VERSION 5.7 ;
  NOWIREEXTENSIONATPIN ON ;
  DIVIDERCHAR "/" ;
  BUSBITCHARS "[]" ;
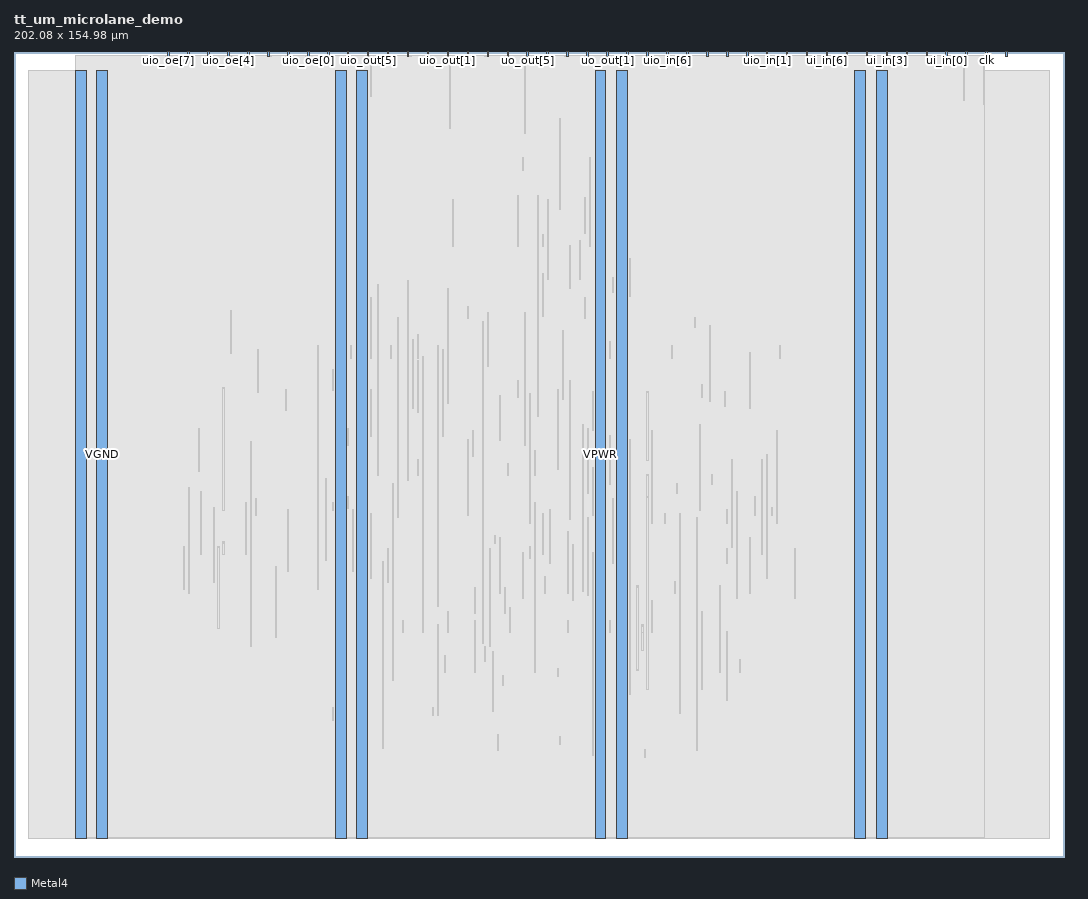
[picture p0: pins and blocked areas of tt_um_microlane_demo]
MACRO tt_um_microlane_demo
  CLASS BLOCK ;
  FOREIGN tt_um_microlane_demo ;
  ORIGIN 0.000 0.000 ;
  SIZE 202.080 BY 154.980 ;
  PIN VPWR
    DIRECTION INOUT ;
    USE POWER ;
    PORT
      LAYER Metal4 ;
        RECT 11.830 3.560 13.930 151.420 ;
    END
    PORT
      LAYER Metal4 ;
        RECT 61.830 3.560 63.930 151.420 ;
    END
    PORT
      LAYER Metal4 ;
        RECT 111.830 3.560 113.930 151.420 ;
    END
    PORT
      LAYER Metal4 ;
        RECT 161.830 3.560 163.930 151.420 ;
    END
  END VPWR
  PIN VGND
    DIRECTION INOUT ;
    USE GROUND ;
    PORT
      LAYER Metal4 ;
        RECT 15.930 3.560 18.030 151.420 ;
    END
    PORT
      LAYER Metal4 ;
        RECT 65.930 3.560 68.030 151.420 ;
    END
    PORT
      LAYER Metal4 ;
        RECT 115.930 3.560 118.030 151.420 ;
    END
    PORT
      LAYER Metal4 ;
        RECT 165.930 3.560 168.030 151.420 ;
    END
  END VGND
  PIN ena
    DIRECTION INPUT ;
    USE SIGNAL ;
    PORT
      LAYER Metal4 ;
        RECT 190.890 153.980 191.190 154.980 ;
    END
  END ena
  PIN clk
    DIRECTION INPUT ;
    USE SIGNAL ;
    PORT
      LAYER Metal4 ;
        RECT 187.050 153.980 187.350 154.980 ;
    END
  END clk
  PIN rst_n
    DIRECTION INPUT ;
    USE SIGNAL ;
    PORT
      LAYER Metal4 ;
        RECT 183.210 153.980 183.510 154.980 ;
    END
  END rst_n
  PIN ui_in[0]
    DIRECTION INPUT ;
    USE SIGNAL ;
    PORT
      LAYER Metal4 ;
        RECT 179.370 153.980 179.670 154.980 ;
    END
  END ui_in[0]
  PIN ui_in[1]
    DIRECTION INPUT ;
    USE SIGNAL ;
    PORT
      LAYER Metal4 ;
        RECT 175.530 153.980 175.830 154.980 ;
    END
  END ui_in[1]
  PIN ui_in[2]
    DIRECTION INPUT ;
    USE SIGNAL ;
    PORT
      LAYER Metal4 ;
        RECT 171.690 153.980 171.990 154.980 ;
    END
  END ui_in[2]
  PIN ui_in[3]
    DIRECTION INPUT ;
    USE SIGNAL ;
    PORT
      LAYER Metal4 ;
        RECT 167.850 153.980 168.150 154.980 ;
    END
  END ui_in[3]
  PIN ui_in[4]
    DIRECTION INPUT ;
    USE SIGNAL ;
    PORT
      LAYER Metal4 ;
        RECT 164.010 153.980 164.310 154.980 ;
    END
  END ui_in[4]
  PIN ui_in[5]
    DIRECTION INPUT ;
    USE SIGNAL ;
    PORT
      LAYER Metal4 ;
        RECT 160.170 153.980 160.470 154.980 ;
    END
  END ui_in[5]
  PIN ui_in[6]
    DIRECTION INPUT ;
    USE SIGNAL ;
    PORT
      LAYER Metal4 ;
        RECT 156.330 153.980 156.630 154.980 ;
    END
  END ui_in[6]
  PIN ui_in[7]
    DIRECTION INPUT ;
    USE SIGNAL ;
    PORT
      LAYER Metal4 ;
        RECT 152.490 153.980 152.790 154.980 ;
    END
  END ui_in[7]
  PIN uio_in[0]
    DIRECTION INPUT ;
    USE SIGNAL ;
    PORT
      LAYER Metal4 ;
        RECT 148.650 153.980 148.950 154.980 ;
    END
  END uio_in[0]
  PIN uio_in[1]
    DIRECTION INPUT ;
    USE SIGNAL ;
    PORT
      LAYER Metal4 ;
        RECT 144.810 153.980 145.110 154.980 ;
    END
  END uio_in[1]
  PIN uio_in[2]
    DIRECTION INPUT ;
    USE SIGNAL ;
    PORT
      LAYER Metal4 ;
        RECT 140.970 153.980 141.270 154.980 ;
    END
  END uio_in[2]
  PIN uio_in[3]
    DIRECTION INPUT ;
    USE SIGNAL ;
    PORT
      LAYER Metal4 ;
        RECT 137.130 153.980 137.430 154.980 ;
    END
  END uio_in[3]
  PIN uio_in[4]
    DIRECTION INPUT ;
    USE SIGNAL ;
    PORT
      LAYER Metal4 ;
        RECT 133.290 153.980 133.590 154.980 ;
    END
  END uio_in[4]
  PIN uio_in[5]
    DIRECTION INPUT ;
    USE SIGNAL ;
    PORT
      LAYER Metal4 ;
        RECT 129.450 153.980 129.750 154.980 ;
    END
  END uio_in[5]
  PIN uio_in[6]
    DIRECTION INPUT ;
    USE SIGNAL ;
    PORT
      LAYER Metal4 ;
        RECT 125.610 153.980 125.910 154.980 ;
    END
  END uio_in[6]
  PIN uio_in[7]
    DIRECTION INPUT ;
    USE SIGNAL ;
    PORT
      LAYER Metal4 ;
        RECT 121.770 153.980 122.070 154.980 ;
    END
  END uio_in[7]
  PIN uo_out[0]
    DIRECTION OUTPUT ;
    USE SIGNAL ;
    PORT
      LAYER Metal4 ;
        RECT 117.930 153.980 118.230 154.980 ;
    END
  END uo_out[0]
  PIN uo_out[1]
    DIRECTION OUTPUT ;
    USE SIGNAL ;
    PORT
      LAYER Metal4 ;
        RECT 114.090 153.980 114.390 154.980 ;
    END
  END uo_out[1]
  PIN uo_out[2]
    DIRECTION OUTPUT ;
    USE SIGNAL ;
    PORT
      LAYER Metal4 ;
        RECT 110.250 153.980 110.550 154.980 ;
    END
  END uo_out[2]
  PIN uo_out[3]
    DIRECTION OUTPUT ;
    USE SIGNAL ;
    PORT
      LAYER Metal4 ;
        RECT 106.410 153.980 106.710 154.980 ;
    END
  END uo_out[3]
  PIN uo_out[4]
    DIRECTION OUTPUT ;
    USE SIGNAL ;
    PORT
      LAYER Metal4 ;
        RECT 102.570 153.980 102.870 154.980 ;
    END
  END uo_out[4]
  PIN uo_out[5]
    DIRECTION OUTPUT ;
    USE SIGNAL ;
    PORT
      LAYER Metal4 ;
        RECT 98.730 153.980 99.030 154.980 ;
    END
  END uo_out[5]
  PIN uo_out[6]
    DIRECTION OUTPUT ;
    USE SIGNAL ;
    PORT
      LAYER Metal4 ;
        RECT 94.890 153.980 95.190 154.980 ;
    END
  END uo_out[6]
  PIN uo_out[7]
    DIRECTION OUTPUT ;
    USE SIGNAL ;
    PORT
      LAYER Metal4 ;
        RECT 91.050 153.980 91.350 154.980 ;
    END
  END uo_out[7]
  PIN uio_out[0]
    DIRECTION OUTPUT ;
    USE SIGNAL ;
    PORT
      LAYER Metal4 ;
        RECT 87.210 153.980 87.510 154.980 ;
    END
  END uio_out[0]
  PIN uio_out[1]
    DIRECTION OUTPUT ;
    USE SIGNAL ;
    PORT
      LAYER Metal4 ;
        RECT 83.370 153.980 83.670 154.980 ;
    END
  END uio_out[1]
  PIN uio_out[2]
    DIRECTION OUTPUT ;
    USE SIGNAL ;
    PORT
      LAYER Metal4 ;
        RECT 79.530 153.980 79.830 154.980 ;
    END
  END uio_out[2]
  PIN uio_out[3]
    DIRECTION OUTPUT ;
    USE SIGNAL ;
    PORT
      LAYER Metal4 ;
        RECT 75.690 153.980 75.990 154.980 ;
    END
  END uio_out[3]
  PIN uio_out[4]
    DIRECTION OUTPUT ;
    USE SIGNAL ;
    PORT
      LAYER Metal4 ;
        RECT 71.850 153.980 72.150 154.980 ;
    END
  END uio_out[4]
  PIN uio_out[5]
    DIRECTION OUTPUT ;
    USE SIGNAL ;
    PORT
      LAYER Metal4 ;
        RECT 68.010 153.980 68.310 154.980 ;
    END
  END uio_out[5]
  PIN uio_out[6]
    DIRECTION OUTPUT ;
    USE SIGNAL ;
    PORT
      LAYER Metal4 ;
        RECT 64.170 153.980 64.470 154.980 ;
    END
  END uio_out[6]
  PIN uio_out[7]
    DIRECTION OUTPUT ;
    USE SIGNAL ;
    PORT
      LAYER Metal4 ;
        RECT 60.330 153.980 60.630 154.980 ;
    END
  END uio_out[7]
  PIN uio_oe[0]
    DIRECTION OUTPUT ;
    USE SIGNAL ;
    PORT
      LAYER Metal4 ;
        RECT 56.490 153.980 56.790 154.980 ;
    END
  END uio_oe[0]
  PIN uio_oe[1]
    DIRECTION OUTPUT ;
    USE SIGNAL ;
    PORT
      LAYER Metal4 ;
        RECT 52.650 153.980 52.950 154.980 ;
    END
  END uio_oe[1]
  PIN uio_oe[2]
    DIRECTION OUTPUT ;
    USE SIGNAL ;
    PORT
      LAYER Metal4 ;
        RECT 48.810 153.980 49.110 154.980 ;
    END
  END uio_oe[2]
  PIN uio_oe[3]
    DIRECTION OUTPUT ;
    USE SIGNAL ;
    PORT
      LAYER Metal4 ;
        RECT 44.970 153.980 45.270 154.980 ;
    END
  END uio_oe[3]
  PIN uio_oe[4]
    DIRECTION OUTPUT ;
    USE SIGNAL ;
    PORT
      LAYER Metal4 ;
        RECT 41.130 153.980 41.430 154.980 ;
    END
  END uio_oe[4]
  PIN uio_oe[5]
    DIRECTION OUTPUT ;
    USE SIGNAL ;
    PORT
      LAYER Metal4 ;
        RECT 37.290 153.980 37.590 154.980 ;
    END
  END uio_oe[5]
  PIN uio_oe[6]
    DIRECTION OUTPUT ;
    USE SIGNAL ;
    PORT
      LAYER Metal4 ;
        RECT 33.450 153.980 33.750 154.980 ;
    END
  END uio_oe[6]
  PIN uio_oe[7]
    DIRECTION OUTPUT ;
    USE SIGNAL ;
    PORT
      LAYER Metal4 ;
        RECT 29.610 153.980 29.910 154.980 ;
    END
  END uio_oe[7]
  OBS
      LAYER GatPoly ;
        RECT 2.880 3.630 199.200 151.350 ;
      LAYER Metal1 ;
        RECT 2.880 3.560 199.200 151.420 ;
      LAYER Metal2 ;
        RECT 11.960 3.635 167.900 154.285 ;
      LAYER Metal3 ;
        RECT 11.915 3.680 186.865 154.320 ;
      LAYER Metal4 ;
        RECT 11.830 3.560 13.930 151.420 ;
        RECT 61.830 3.560 63.930 151.420 ;
        RECT 111.830 3.560 113.930 151.420 ;
        RECT 161.830 3.560 163.930 151.420 ;
        RECT 15.930 3.560 18.030 151.420 ;
        RECT 65.930 3.560 68.030 151.420 ;
        RECT 115.930 3.560 118.030 151.420 ;
        RECT 165.930 3.560 168.030 151.420 ;
        RECT 190.890 153.980 191.190 154.980 ;
        RECT 187.050 153.980 187.350 154.980 ;
        RECT 183.210 153.980 183.510 154.980 ;
        RECT 179.370 153.980 179.670 154.980 ;
        RECT 175.530 153.980 175.830 154.980 ;
        RECT 171.690 153.980 171.990 154.980 ;
        RECT 167.850 153.980 168.150 154.980 ;
        RECT 164.010 153.980 164.310 154.980 ;
        RECT 160.170 153.980 160.470 154.980 ;
        RECT 156.330 153.980 156.630 154.980 ;
        RECT 152.490 153.980 152.790 154.980 ;
        RECT 148.650 153.980 148.950 154.980 ;
        RECT 144.810 153.980 145.110 154.980 ;
        RECT 140.970 153.980 141.270 154.980 ;
        RECT 137.130 153.980 137.430 154.980 ;
        RECT 133.290 153.980 133.590 154.980 ;
        RECT 129.450 153.980 129.750 154.980 ;
        RECT 125.610 153.980 125.910 154.980 ;
        RECT 121.770 153.980 122.070 154.980 ;
        RECT 117.930 153.980 118.230 154.980 ;
        RECT 114.090 153.980 114.390 154.980 ;
        RECT 110.250 153.980 110.550 154.980 ;
        RECT 106.410 153.980 106.710 154.980 ;
        RECT 102.570 153.980 102.870 154.980 ;
        RECT 98.730 153.980 99.030 154.980 ;
        RECT 94.890 153.980 95.190 154.980 ;
        RECT 91.050 153.980 91.350 154.980 ;
        RECT 87.210 153.980 87.510 154.980 ;
        RECT 83.370 153.980 83.670 154.980 ;
        RECT 79.530 153.980 79.830 154.980 ;
        RECT 75.690 153.980 75.990 154.980 ;
        RECT 71.850 153.980 72.150 154.980 ;
        RECT 68.010 153.980 68.310 154.980 ;
        RECT 64.170 153.980 64.470 154.980 ;
        RECT 60.330 153.980 60.630 154.980 ;
        RECT 56.490 153.980 56.790 154.980 ;
        RECT 52.650 153.980 52.950 154.980 ;
        RECT 48.810 153.980 49.110 154.980 ;
        RECT 44.970 153.980 45.270 154.980 ;
        RECT 41.130 153.980 41.430 154.980 ;
        RECT 37.290 153.980 37.590 154.980 ;
        RECT 33.450 153.980 33.750 154.980 ;
        RECT 29.610 153.980 29.910 154.980 ;
        RECT 110.780 134.255 110.980 134.545 ;
        RECT 110.780 117.455 110.980 117.745 ;
        RECT 110.780 117.500 110.980 117.700 ;
        RECT 110.780 117.500 110.980 134.500 ;
        RECT 110.780 134.300 110.980 134.500 ;
        RECT 105.020 141.815 105.220 142.105 ;
        RECT 105.020 124.595 105.220 124.885 ;
        RECT 105.020 124.640 105.220 124.840 ;
        RECT 105.020 124.640 105.220 142.060 ;
        RECT 105.020 141.860 105.220 142.060 ;
        RECT 97.820 134.255 98.020 134.545 ;
        RECT 97.820 132.155 98.020 132.445 ;
        RECT 97.820 132.200 98.020 132.400 ;
        RECT 97.820 132.200 98.020 134.500 ;
        RECT 97.820 134.300 98.020 134.500 ;
        RECT 81.500 27.155 81.700 27.445 ;
        RECT 81.500 27.200 81.700 27.400 ;
        RECT 81.500 27.200 81.700 44.620 ;
        RECT 81.500 33.875 81.700 34.165 ;
        RECT 81.500 33.920 81.700 34.120 ;
        RECT 81.500 44.375 81.700 44.665 ;
        RECT 81.500 44.420 81.700 44.620 ;
        RECT 82.940 35.555 83.140 35.845 ;
        RECT 82.940 35.600 83.140 35.800 ;
        RECT 82.940 35.600 83.140 38.740 ;
        RECT 82.940 38.495 83.140 38.785 ;
        RECT 82.940 38.540 83.140 38.740 ;
        RECT 139.580 35.555 139.780 35.845 ;
        RECT 139.580 35.600 139.780 35.800 ;
        RECT 139.580 35.600 139.780 37.900 ;
        RECT 139.580 37.655 139.780 37.945 ;
        RECT 139.580 37.700 139.780 37.900 ;
        RECT 104.540 35.975 104.740 36.265 ;
        RECT 104.540 34.715 104.740 35.005 ;
        RECT 104.540 34.760 104.740 34.960 ;
        RECT 104.540 34.760 104.740 36.220 ;
        RECT 104.540 36.020 104.740 36.220 ;
        RECT 80.540 28.415 80.740 28.705 ;
        RECT 80.540 27.155 80.740 27.445 ;
        RECT 80.540 27.200 80.740 27.400 ;
        RECT 80.540 27.200 80.740 28.660 ;
        RECT 80.540 28.460 80.740 28.660 ;
        RECT 114.620 43.115 114.820 43.405 ;
        RECT 114.620 43.160 114.820 43.360 ;
        RECT 114.620 43.160 114.820 45.460 ;
        RECT 114.620 45.215 114.820 45.505 ;
        RECT 114.620 45.260 114.820 45.460 ;
        RECT 137.180 59.075 137.380 59.365 ;
        RECT 137.180 56.555 137.380 56.845 ;
        RECT 137.180 56.600 137.380 56.800 ;
        RECT 137.180 56.600 137.380 59.320 ;
        RECT 137.180 59.120 137.380 59.320 ;
        RECT 61.340 28.415 61.540 28.705 ;
        RECT 61.340 26.315 61.540 26.605 ;
        RECT 61.340 26.360 61.540 26.560 ;
        RECT 61.340 26.360 61.540 28.660 ;
        RECT 61.340 28.460 61.540 28.660 ;
        RECT 91.580 43.115 91.780 43.405 ;
        RECT 91.580 40.595 91.780 40.885 ;
        RECT 91.580 40.640 91.780 40.840 ;
        RECT 91.580 40.640 91.780 43.360 ;
        RECT 91.580 43.160 91.780 43.360 ;
        RECT 91.580 43.160 91.780 59.320 ;
        RECT 91.580 59.075 91.780 59.365 ;
        RECT 91.580 59.120 91.780 59.320 ;
        RECT 137.180 43.115 137.380 43.405 ;
        RECT 137.180 30.095 137.380 30.385 ;
        RECT 137.180 30.140 137.380 30.340 ;
        RECT 137.180 30.140 137.380 43.360 ;
        RECT 137.180 40.595 137.380 40.885 ;
        RECT 137.180 40.640 137.380 40.840 ;
        RECT 137.180 43.160 137.380 43.360 ;
        RECT 122.780 43.115 122.980 43.405 ;
        RECT 122.780 43.160 122.980 43.360 ;
        RECT 122.780 43.160 122.980 49.240 ;
        RECT 122.780 48.995 122.980 49.285 ;
        RECT 122.780 49.040 122.980 49.240 ;
        RECT 127.100 50.675 127.300 50.965 ;
        RECT 127.100 50.720 127.300 50.920 ;
        RECT 127.100 50.720 127.300 53.020 ;
        RECT 127.100 52.775 127.300 53.065 ;
        RECT 127.100 52.820 127.300 53.020 ;
        RECT 150.140 59.075 150.340 59.365 ;
        RECT 150.140 49.835 150.340 50.125 ;
        RECT 150.140 49.880 150.340 50.080 ;
        RECT 150.140 49.880 150.340 59.320 ;
        RECT 150.140 52.775 150.340 53.065 ;
        RECT 150.140 52.820 150.340 53.020 ;
        RECT 150.140 59.120 150.340 59.320 ;
        RECT 108.860 111.155 109.060 111.445 ;
        RECT 108.860 111.200 109.060 111.400 ;
        RECT 108.860 111.200 109.060 118.540 ;
        RECT 108.860 118.295 109.060 118.585 ;
        RECT 108.860 118.340 109.060 118.540 ;
        RECT 115.100 111.155 115.300 111.445 ;
        RECT 115.100 108.635 115.300 108.925 ;
        RECT 115.100 108.680 115.300 108.880 ;
        RECT 115.100 108.680 115.300 111.400 ;
        RECT 115.100 111.200 115.300 111.400 ;
        RECT 102.620 111.155 102.820 111.445 ;
        RECT 102.620 111.200 102.820 111.400 ;
        RECT 102.620 111.200 102.820 116.440 ;
        RECT 102.620 116.195 102.820 116.485 ;
        RECT 102.620 116.240 102.820 116.440 ;
        RECT 102.620 116.240 102.820 126.520 ;
        RECT 102.620 123.755 102.820 124.045 ;
        RECT 102.620 123.800 102.820 124.000 ;
        RECT 102.620 126.275 102.820 126.565 ;
        RECT 102.620 126.320 102.820 126.520 ;
        RECT 120.860 43.115 121.060 43.405 ;
        RECT 120.860 39.755 121.060 40.045 ;
        RECT 120.860 39.800 121.060 40.000 ;
        RECT 120.860 39.800 121.060 43.360 ;
        RECT 120.860 43.160 121.060 43.360 ;
        RECT 120.860 43.160 121.060 44.620 ;
        RECT 120.860 44.375 121.060 44.665 ;
        RECT 120.860 44.420 121.060 44.620 ;
        RECT 64.700 96.035 64.900 96.325 ;
        RECT 64.700 96.080 64.900 96.280 ;
        RECT 64.700 96.080 64.900 98.380 ;
        RECT 64.700 98.135 64.900 98.425 ;
        RECT 64.700 98.180 64.900 98.380 ;
        RECT 105.500 96.035 105.700 96.325 ;
        RECT 105.500 88.055 105.700 88.345 ;
        RECT 105.500 88.100 105.700 88.300 ;
        RECT 105.500 88.100 105.700 96.280 ;
        RECT 105.500 96.080 105.700 96.280 ;
        RECT 105.500 96.080 105.700 101.320 ;
        RECT 105.500 101.075 105.700 101.365 ;
        RECT 105.500 101.120 105.700 101.320 ;
        RECT 132.380 88.475 132.580 88.765 ;
        RECT 132.380 88.520 132.580 88.720 ;
        RECT 132.380 88.520 132.580 90.820 ;
        RECT 132.380 90.575 132.580 90.865 ;
        RECT 132.380 90.620 132.580 90.820 ;
        RECT 74.780 43.115 74.980 43.405 ;
        RECT 74.780 43.160 74.980 43.360 ;
        RECT 74.780 43.160 74.980 45.460 ;
        RECT 74.780 45.215 74.980 45.505 ;
        RECT 74.780 45.260 74.980 45.460 ;
        RECT 88.700 35.555 88.900 35.845 ;
        RECT 88.700 35.600 88.900 35.800 ;
        RECT 88.700 35.600 88.900 45.460 ;
        RECT 88.700 45.215 88.900 45.505 ;
        RECT 88.700 45.260 88.900 45.460 ;
        RECT 101.660 58.235 101.860 58.525 ;
        RECT 101.660 58.280 101.860 58.480 ;
        RECT 101.660 58.280 101.860 66.040 ;
        RECT 101.660 65.795 101.860 66.085 ;
        RECT 101.660 65.840 101.860 66.040 ;
        RECT 83.420 43.115 83.620 43.405 ;
        RECT 83.420 43.160 83.620 43.360 ;
        RECT 83.420 43.160 83.620 47.140 ;
        RECT 83.420 46.895 83.620 47.185 ;
        RECT 83.420 46.940 83.620 47.140 ;
        RECT 88.700 51.515 88.900 51.805 ;
        RECT 88.700 46.895 88.900 47.185 ;
        RECT 88.700 46.940 88.900 47.140 ;
        RECT 88.700 46.940 88.900 51.760 ;
        RECT 88.700 51.560 88.900 51.760 ;
        RECT 111.260 89.315 111.460 89.605 ;
        RECT 111.260 82.175 111.460 82.465 ;
        RECT 111.260 82.220 111.460 82.420 ;
        RECT 111.260 82.220 111.460 89.560 ;
        RECT 111.260 89.360 111.460 89.560 ;
        RECT 146.780 81.755 146.980 82.045 ;
        RECT 146.780 64.115 146.980 64.405 ;
        RECT 146.780 64.160 146.980 64.360 ;
        RECT 146.780 64.160 146.980 82.000 ;
        RECT 146.780 75.455 146.980 75.745 ;
        RECT 146.780 75.500 146.980 75.700 ;
        RECT 146.780 81.800 146.980 82.000 ;
        RECT 68.540 65.795 68.740 66.085 ;
        RECT 68.540 53.615 68.740 53.905 ;
        RECT 68.540 53.660 68.740 53.860 ;
        RECT 68.540 53.660 68.740 66.040 ;
        RECT 68.540 65.840 68.740 66.040 ;
        RECT 102.140 50.675 102.340 50.965 ;
        RECT 102.140 50.720 102.340 50.920 ;
        RECT 102.140 50.720 102.340 53.860 ;
        RECT 102.140 53.615 102.340 53.905 ;
        RECT 102.140 53.660 102.340 53.860 ;
        RECT 95.420 43.115 95.620 43.405 ;
        RECT 95.420 43.160 95.620 43.360 ;
        RECT 95.420 43.160 95.620 47.980 ;
        RECT 95.420 47.735 95.620 48.025 ;
        RECT 95.420 47.780 95.620 47.980 ;
        RECT 121.820 89.315 122.020 89.605 ;
        RECT 121.820 76.295 122.020 76.585 ;
        RECT 121.820 76.340 122.020 76.540 ;
        RECT 121.820 76.340 122.020 89.560 ;
        RECT 121.820 89.360 122.020 89.560 ;
        RECT 138.140 74.195 138.340 74.485 ;
        RECT 138.140 59.495 138.340 59.785 ;
        RECT 138.140 59.540 138.340 59.740 ;
        RECT 138.140 59.540 138.340 74.440 ;
        RECT 138.140 74.240 138.340 74.440 ;
        RECT 138.140 74.240 138.340 76.540 ;
        RECT 138.140 76.295 138.340 76.585 ;
        RECT 138.140 76.340 138.340 76.540 ;
        RECT 145.820 65.795 146.020 66.085 ;
        RECT 145.820 65.840 146.020 66.040 ;
        RECT 145.820 65.840 146.020 67.300 ;
        RECT 145.820 67.055 146.020 67.345 ;
        RECT 145.820 67.100 146.020 67.300 ;
        RECT 93.020 20.435 93.220 20.725 ;
        RECT 93.020 20.480 93.220 20.680 ;
        RECT 93.020 20.480 93.220 23.620 ;
        RECT 93.020 23.375 93.220 23.665 ;
        RECT 93.020 23.420 93.220 23.620 ;
        RECT 106.460 50.675 106.660 50.965 ;
        RECT 106.460 50.720 106.660 50.920 ;
        RECT 106.460 50.720 106.660 62.680 ;
        RECT 106.460 62.435 106.660 62.725 ;
        RECT 106.460 62.480 106.660 62.680 ;
        RECT 88.220 81.755 88.420 82.045 ;
        RECT 88.220 77.135 88.420 77.425 ;
        RECT 88.220 77.180 88.420 77.380 ;
        RECT 88.220 77.180 88.420 82.000 ;
        RECT 88.220 81.800 88.420 82.000 ;
        RECT 144.860 74.195 145.060 74.485 ;
        RECT 144.860 53.615 145.060 53.905 ;
        RECT 144.860 53.660 145.060 53.860 ;
        RECT 144.860 53.660 145.060 74.440 ;
        RECT 144.860 74.240 145.060 74.440 ;
        RECT 144.860 74.240 145.060 77.380 ;
        RECT 144.860 77.135 145.060 77.425 ;
        RECT 144.860 77.180 145.060 77.380 ;
        RECT 143.900 58.235 144.100 58.525 ;
        RECT 143.900 58.280 144.100 58.480 ;
        RECT 143.900 58.280 144.100 76.540 ;
        RECT 143.900 76.295 144.100 76.585 ;
        RECT 143.900 76.340 144.100 76.540 ;
        RECT 50.300 50.675 50.500 50.965 ;
        RECT 50.300 42.275 50.500 42.565 ;
        RECT 50.300 42.320 50.500 42.520 ;
        RECT 50.300 42.320 50.500 50.920 ;
        RECT 50.300 50.720 50.500 50.920 ;
        RECT 50.300 50.720 50.500 55.960 ;
        RECT 50.300 55.715 50.500 56.005 ;
        RECT 50.300 55.760 50.500 55.960 ;
        RECT 94.460 51.515 94.660 51.805 ;
        RECT 94.460 46.895 94.660 47.185 ;
        RECT 94.460 46.940 94.660 47.140 ;
        RECT 94.460 46.940 94.660 51.760 ;
        RECT 94.460 51.560 94.660 51.760 ;
        RECT 122.780 81.755 122.980 82.045 ;
        RECT 122.780 64.115 122.980 64.405 ;
        RECT 122.780 64.160 122.980 64.360 ;
        RECT 122.780 64.160 122.980 82.000 ;
        RECT 122.780 81.800 122.980 82.000 ;
        RECT 111.260 58.235 111.460 58.525 ;
        RECT 111.260 19.595 111.460 19.885 ;
        RECT 111.260 19.640 111.460 19.840 ;
        RECT 111.260 19.640 111.460 58.480 ;
        RECT 111.260 32.195 111.460 32.485 ;
        RECT 111.260 32.240 111.460 32.440 ;
        RECT 111.260 58.280 111.460 58.480 ;
        RECT 121.340 19.175 121.540 19.465 ;
        RECT 121.340 19.220 121.540 19.420 ;
        RECT 121.340 19.220 121.540 20.680 ;
        RECT 121.340 20.435 121.540 20.725 ;
        RECT 121.340 20.480 121.540 20.680 ;
        RECT 131.420 58.235 131.620 58.525 ;
        RECT 131.420 20.435 131.620 20.725 ;
        RECT 131.420 20.480 131.620 20.680 ;
        RECT 131.420 20.480 131.620 58.480 ;
        RECT 131.420 58.280 131.620 58.480 ;
        RECT 131.420 58.280 131.620 65.200 ;
        RECT 131.420 64.955 131.620 65.245 ;
        RECT 131.420 65.000 131.620 65.200 ;
        RECT 93.500 50.675 93.700 50.965 ;
        RECT 93.500 50.720 93.700 50.920 ;
        RECT 93.500 50.720 93.700 59.740 ;
        RECT 93.500 59.495 93.700 59.785 ;
        RECT 93.500 59.540 93.700 59.740 ;
        RECT 93.500 59.540 93.700 61.420 ;
        RECT 93.500 61.175 93.700 61.465 ;
        RECT 93.500 61.220 93.700 61.420 ;
        RECT 141.500 58.235 141.700 58.525 ;
        RECT 141.500 50.675 141.700 50.965 ;
        RECT 141.500 50.720 141.700 50.920 ;
        RECT 141.500 50.720 141.700 58.480 ;
        RECT 141.500 58.280 141.700 58.480 ;
        RECT 141.500 58.280 141.700 61.420 ;
        RECT 141.500 61.175 141.700 61.465 ;
        RECT 141.500 61.220 141.700 61.420 ;
        RECT 137.180 66.635 137.380 66.925 ;
        RECT 137.180 64.115 137.380 64.405 ;
        RECT 137.180 64.160 137.380 64.360 ;
        RECT 137.180 64.160 137.380 66.880 ;
        RECT 137.180 66.680 137.380 66.880 ;
        RECT 134.300 73.355 134.500 73.645 ;
        RECT 134.300 71.675 134.500 71.965 ;
        RECT 134.300 71.720 134.500 71.920 ;
        RECT 134.300 71.720 134.500 73.600 ;
        RECT 134.300 73.400 134.500 73.600 ;
        RECT 33.500 50.675 33.700 50.965 ;
        RECT 33.500 50.720 33.700 50.920 ;
        RECT 33.500 50.720 33.700 71.080 ;
        RECT 33.500 70.835 33.700 71.125 ;
        RECT 33.500 70.880 33.700 71.080 ;
        RECT 128.060 35.555 128.260 35.845 ;
        RECT 128.060 27.575 128.260 27.865 ;
        RECT 128.060 27.620 128.260 27.820 ;
        RECT 128.060 27.620 128.260 35.800 ;
        RECT 128.060 35.600 128.260 35.800 ;
        RECT 128.060 35.600 128.260 66.040 ;
        RECT 128.060 65.795 128.260 66.085 ;
        RECT 128.060 65.840 128.260 66.040 ;
        RECT 135.740 35.555 135.940 35.845 ;
        RECT 135.740 35.600 135.940 35.800 ;
        RECT 135.740 35.600 135.940 52.180 ;
        RECT 135.740 51.935 135.940 52.225 ;
        RECT 135.740 51.980 135.940 52.180 ;
        RECT 35.900 58.235 36.100 58.525 ;
        RECT 35.900 58.280 36.100 58.480 ;
        RECT 35.900 58.280 36.100 70.240 ;
        RECT 35.900 69.995 36.100 70.285 ;
        RECT 35.900 70.040 36.100 70.240 ;
        RECT 107.420 59.915 107.620 60.205 ;
        RECT 107.420 49.415 107.620 49.705 ;
        RECT 107.420 49.460 107.620 49.660 ;
        RECT 107.420 49.460 107.620 60.160 ;
        RECT 107.420 59.960 107.620 60.160 ;
        RECT 45.500 73.355 45.700 73.645 ;
        RECT 45.500 40.595 45.700 40.885 ;
        RECT 45.500 40.640 45.700 40.840 ;
        RECT 45.500 40.640 45.700 73.600 ;
        RECT 45.500 73.400 45.700 73.600 ;
        RECT 45.500 73.400 45.700 79.900 ;
        RECT 45.500 79.655 45.700 79.945 ;
        RECT 45.500 79.700 45.700 79.900 ;
        RECT 118.460 50.675 118.660 50.965 ;
        RECT 118.460 31.355 118.660 31.645 ;
        RECT 118.460 31.400 118.660 31.600 ;
        RECT 118.460 31.400 118.660 50.920 ;
        RECT 118.460 50.720 118.660 50.920 ;
        RECT 118.460 50.720 118.660 80.320 ;
        RECT 118.460 80.075 118.660 80.365 ;
        RECT 118.460 80.120 118.660 80.320 ;
        RECT 40.220 58.235 40.420 58.525 ;
        RECT 40.220 58.280 40.420 58.480 ;
        RECT 40.220 58.280 40.420 60.580 ;
        RECT 40.220 60.335 40.420 60.625 ;
        RECT 40.220 60.380 40.420 60.580 ;
        RECT 96.860 88.475 97.060 88.765 ;
        RECT 96.860 88.520 97.060 88.720 ;
        RECT 96.860 88.520 97.060 91.660 ;
        RECT 96.860 91.415 97.060 91.705 ;
        RECT 96.860 91.460 97.060 91.660 ;
        RECT 106.940 80.915 107.140 81.205 ;
        RECT 106.940 64.955 107.140 65.245 ;
        RECT 106.940 65.000 107.140 65.200 ;
        RECT 106.940 65.000 107.140 81.160 ;
        RECT 106.940 80.960 107.140 81.160 ;
        RECT 106.940 80.960 107.140 91.660 ;
        RECT 106.940 91.415 107.140 91.705 ;
        RECT 106.940 91.460 107.140 91.660 ;
        RECT 110.300 50.255 110.500 50.545 ;
        RECT 110.300 50.300 110.500 50.500 ;
        RECT 110.300 50.300 110.500 65.200 ;
        RECT 110.300 64.955 110.500 65.245 ;
        RECT 110.300 65.000 110.500 65.200 ;
        RECT 106.460 43.115 106.660 43.405 ;
        RECT 106.460 43.160 106.660 43.360 ;
        RECT 106.460 43.160 106.660 45.460 ;
        RECT 106.460 45.215 106.660 45.505 ;
        RECT 106.460 45.260 106.660 45.460 ;
        RECT 114.620 80.915 114.820 81.205 ;
        RECT 114.620 71.675 114.820 71.965 ;
        RECT 114.620 71.720 114.820 71.920 ;
        RECT 114.620 71.720 114.820 81.160 ;
        RECT 114.620 80.960 114.820 81.160 ;
        RECT 94.940 73.355 95.140 73.645 ;
        RECT 94.940 73.400 95.140 73.600 ;
        RECT 94.940 73.400 95.140 75.700 ;
        RECT 94.940 75.455 95.140 75.745 ;
        RECT 94.940 75.500 95.140 75.700 ;
        RECT 44.540 58.235 44.740 58.525 ;
        RECT 44.540 58.280 44.740 58.480 ;
        RECT 44.540 58.280 44.740 68.140 ;
        RECT 44.540 67.895 44.740 68.185 ;
        RECT 44.540 67.940 44.740 68.140 ;
        RECT 87.260 65.795 87.460 66.085 ;
        RECT 87.260 65.840 87.460 66.040 ;
        RECT 87.260 65.840 87.460 80.320 ;
        RECT 87.260 80.075 87.460 80.365 ;
        RECT 87.260 80.120 87.460 80.320 ;
        RECT 93.500 88.475 93.700 88.765 ;
        RECT 93.500 80.075 93.700 80.365 ;
        RECT 93.500 80.120 93.700 80.320 ;
        RECT 93.500 80.120 93.700 88.720 ;
        RECT 93.500 88.520 93.700 88.720 ;
        RECT 77.660 73.355 77.860 73.645 ;
        RECT 77.660 73.400 77.860 73.600 ;
        RECT 77.660 73.400 77.860 76.540 ;
        RECT 77.660 76.295 77.860 76.585 ;
        RECT 77.660 76.340 77.860 76.540 ;
        RECT 46.460 65.795 46.660 66.085 ;
        RECT 46.460 65.840 46.660 66.040 ;
        RECT 46.460 65.840 46.660 68.980 ;
        RECT 46.460 68.735 46.660 69.025 ;
        RECT 46.460 68.780 46.660 68.980 ;
        RECT 97.820 58.235 98.020 58.525 ;
        RECT 97.820 49.835 98.020 50.125 ;
        RECT 97.820 49.880 98.020 50.080 ;
        RECT 97.820 49.880 98.020 58.480 ;
        RECT 97.820 58.280 98.020 58.480 ;
        RECT 92.540 61.595 92.740 61.885 ;
        RECT 92.540 60.335 92.740 60.625 ;
        RECT 92.540 60.380 92.740 60.580 ;
        RECT 92.540 60.380 92.740 61.840 ;
        RECT 92.540 61.640 92.740 61.840 ;
        RECT 77.660 96.035 77.860 96.325 ;
        RECT 77.660 96.080 77.860 96.280 ;
        RECT 77.660 96.080 77.860 100.480 ;
        RECT 77.660 100.235 77.860 100.525 ;
        RECT 77.660 100.280 77.860 100.480 ;
        RECT 78.620 43.115 78.820 43.405 ;
        RECT 78.620 43.160 78.820 43.360 ;
        RECT 78.620 43.160 78.820 96.280 ;
        RECT 78.620 96.035 78.820 96.325 ;
        RECT 78.620 96.080 78.820 96.280 ;
        RECT 91.100 104.435 91.300 104.725 ;
        RECT 91.100 94.355 91.300 94.645 ;
        RECT 91.100 94.400 91.300 94.600 ;
        RECT 91.100 94.400 91.300 104.680 ;
        RECT 91.100 104.480 91.300 104.680 ;
        RECT 87.260 103.595 87.460 103.885 ;
        RECT 87.260 103.640 87.460 103.840 ;
        RECT 87.260 103.640 87.460 105.940 ;
        RECT 87.260 105.695 87.460 105.985 ;
        RECT 87.260 105.740 87.460 105.940 ;
        RECT 83.420 96.035 83.620 96.325 ;
        RECT 83.420 87.215 83.620 87.505 ;
        RECT 83.420 87.260 83.620 87.460 ;
        RECT 83.420 87.260 83.620 96.280 ;
        RECT 83.420 96.080 83.620 96.280 ;
        RECT 83.420 96.080 83.620 109.300 ;
        RECT 83.420 109.055 83.620 109.345 ;
        RECT 83.420 109.100 83.620 109.300 ;
        RECT 114.620 96.035 114.820 96.325 ;
        RECT 114.620 96.080 114.820 96.280 ;
        RECT 114.620 96.080 114.820 99.220 ;
        RECT 114.620 98.975 114.820 99.265 ;
        RECT 114.620 99.020 114.820 99.220 ;
        RECT 77.660 88.475 77.860 88.765 ;
        RECT 77.660 85.535 77.860 85.825 ;
        RECT 77.660 85.580 77.860 85.780 ;
        RECT 77.660 85.580 77.860 88.720 ;
        RECT 77.660 88.520 77.860 88.720 ;
        RECT 77.660 88.520 77.860 95.440 ;
        RECT 77.660 95.195 77.860 95.485 ;
        RECT 77.660 95.240 77.860 95.440 ;
        RECT 76.700 96.875 76.900 97.165 ;
        RECT 76.700 86.375 76.900 86.665 ;
        RECT 76.700 86.420 76.900 86.620 ;
        RECT 76.700 86.420 76.900 97.120 ;
        RECT 76.700 96.920 76.900 97.120 ;
        RECT 76.700 96.920 76.900 99.640 ;
        RECT 76.700 99.395 76.900 99.685 ;
        RECT 76.700 99.440 76.900 99.640 ;
        RECT 72.380 96.035 72.580 96.325 ;
        RECT 72.380 96.080 72.580 96.280 ;
        RECT 72.380 96.080 72.580 98.380 ;
        RECT 72.380 98.135 72.580 98.425 ;
        RECT 72.380 98.180 72.580 98.380 ;
        RECT 61.340 89.735 61.540 90.025 ;
        RECT 61.340 89.780 61.540 89.980 ;
        RECT 61.340 89.780 61.540 93.760 ;
        RECT 61.340 93.515 61.540 93.805 ;
        RECT 61.340 93.560 61.540 93.760 ;
        RECT 136.700 89.315 136.900 89.605 ;
        RECT 136.700 86.795 136.900 87.085 ;
        RECT 136.700 86.840 136.900 87.040 ;
        RECT 136.700 86.840 136.900 89.560 ;
        RECT 136.700 89.360 136.900 89.560 ;
        RECT 126.620 96.035 126.820 96.325 ;
        RECT 126.620 96.080 126.820 96.280 ;
        RECT 126.620 96.080 126.820 98.380 ;
        RECT 126.620 98.135 126.820 98.425 ;
        RECT 126.620 98.180 126.820 98.380 ;
        RECT 141.500 96.875 141.700 97.165 ;
        RECT 141.500 86.375 141.700 86.665 ;
        RECT 141.500 86.420 141.700 86.620 ;
        RECT 141.500 86.420 141.700 97.120 ;
        RECT 141.500 96.920 141.700 97.120 ;
        RECT 147.260 96.035 147.460 96.325 ;
        RECT 147.260 96.080 147.460 96.280 ;
        RECT 147.260 96.080 147.460 98.380 ;
        RECT 147.260 98.135 147.460 98.425 ;
        RECT 147.260 98.180 147.460 98.380 ;
        RECT 40.220 66.635 40.420 66.925 ;
        RECT 40.220 66.680 40.420 66.880 ;
        RECT 40.220 66.680 40.420 90.400 ;
        RECT 40.220 90.155 40.420 90.445 ;
        RECT 40.220 90.200 40.420 90.400 ;
        RECT 41.660 96.875 41.860 97.165 ;
        RECT 41.660 96.920 41.860 97.120 ;
        RECT 41.660 96.920 41.860 105.100 ;
        RECT 41.660 104.855 41.860 105.145 ;
        RECT 41.660 104.900 41.860 105.100 ;
        RECT 82.460 80.915 82.660 81.205 ;
        RECT 82.460 80.960 82.660 81.160 ;
        RECT 82.460 80.960 82.660 97.540 ;
        RECT 82.460 97.295 82.660 97.585 ;
        RECT 82.460 97.340 82.660 97.540 ;
        RECT 64.220 79.235 64.420 79.525 ;
        RECT 64.220 79.280 64.420 79.480 ;
        RECT 64.220 79.280 64.420 82.420 ;
        RECT 64.220 82.175 64.420 82.465 ;
        RECT 64.220 82.220 64.420 82.420 ;
        RECT 68.540 80.915 68.740 81.205 ;
        RECT 68.540 80.960 68.740 81.160 ;
        RECT 68.540 80.960 68.740 89.980 ;
        RECT 68.540 89.735 68.740 90.025 ;
        RECT 68.540 89.780 68.740 89.980 ;
        RECT 46.940 89.315 47.140 89.605 ;
        RECT 46.940 89.360 47.140 89.560 ;
        RECT 46.940 89.360 47.140 97.540 ;
        RECT 46.940 97.295 47.140 97.585 ;
        RECT 46.940 97.340 47.140 97.540 ;
        RECT 109.340 51.095 109.540 51.385 ;
        RECT 109.340 51.140 109.540 51.340 ;
        RECT 109.340 51.140 109.540 83.260 ;
        RECT 109.340 83.015 109.540 83.305 ;
        RECT 109.340 83.060 109.540 83.260 ;
        RECT 100.220 35.555 100.420 35.845 ;
        RECT 100.220 35.600 100.420 35.800 ;
        RECT 100.220 35.600 100.420 68.140 ;
        RECT 100.220 67.895 100.420 68.185 ;
        RECT 100.220 67.940 100.420 68.140 ;
        RECT 39.260 43.955 39.460 44.245 ;
        RECT 39.260 44.000 39.460 44.200 ;
        RECT 39.260 44.000 39.460 59.740 ;
        RECT 39.260 59.495 39.460 59.785 ;
        RECT 39.260 59.540 39.460 59.740 ;
        RECT 52.220 85.955 52.420 86.245 ;
        RECT 52.220 86.000 52.420 86.200 ;
        RECT 52.220 86.000 52.420 89.980 ;
        RECT 52.220 89.735 52.420 90.025 ;
        RECT 52.220 89.780 52.420 89.980 ;
        RECT 110.300 69.995 110.500 70.285 ;
        RECT 110.300 70.040 110.500 70.240 ;
        RECT 110.300 70.040 110.500 82.420 ;
        RECT 110.300 82.175 110.500 82.465 ;
        RECT 110.300 82.220 110.500 82.420 ;
        RECT 104.540 74.615 104.740 74.905 ;
        RECT 104.540 74.660 104.740 74.860 ;
        RECT 104.540 74.660 104.740 89.980 ;
        RECT 104.540 89.735 104.740 90.025 ;
        RECT 104.540 89.780 104.740 89.980 ;
        RECT 119.900 35.975 120.100 36.265 ;
        RECT 119.900 36.020 120.100 36.220 ;
        RECT 119.900 36.020 120.100 52.180 ;
        RECT 119.900 51.935 120.100 52.225 ;
        RECT 119.900 51.980 120.100 52.180 ;
        RECT 35.420 74.195 35.620 74.485 ;
        RECT 35.420 74.240 35.620 74.440 ;
        RECT 35.420 74.240 35.620 82.420 ;
        RECT 35.420 82.175 35.620 82.465 ;
        RECT 35.420 82.220 35.620 82.420 ;
        RECT 32.540 51.515 32.740 51.805 ;
        RECT 32.540 51.560 32.740 51.760 ;
        RECT 32.540 51.560 32.740 59.740 ;
        RECT 32.540 59.495 32.740 59.785 ;
        RECT 32.540 59.540 32.740 59.740 ;
        RECT 131.900 66.635 132.100 66.925 ;
        RECT 131.900 66.680 132.100 66.880 ;
        RECT 131.900 66.680 132.100 83.260 ;
        RECT 131.900 83.015 132.100 83.305 ;
        RECT 131.900 83.060 132.100 83.260 ;
        RECT 111.260 65.795 111.460 66.085 ;
        RECT 111.260 65.840 111.460 66.040 ;
        RECT 111.260 65.840 111.460 74.860 ;
        RECT 111.260 74.615 111.460 74.905 ;
        RECT 111.260 74.660 111.460 74.860 ;
        RECT 38.300 52.775 38.500 53.065 ;
        RECT 38.300 52.820 38.500 53.020 ;
        RECT 38.300 52.820 38.500 67.300 ;
        RECT 38.300 67.055 38.500 67.345 ;
        RECT 38.300 67.100 38.500 67.300 ;
        RECT 105.020 22.955 105.220 23.245 ;
        RECT 105.020 21.695 105.220 21.985 ;
        RECT 105.020 21.740 105.220 21.940 ;
        RECT 105.020 21.740 105.220 23.200 ;
        RECT 105.020 23.000 105.220 23.200 ;
        RECT 52.700 66.635 52.900 66.925 ;
        RECT 52.700 54.875 52.900 55.165 ;
        RECT 52.700 54.920 52.900 55.120 ;
        RECT 52.700 54.920 52.900 66.880 ;
        RECT 52.700 66.680 52.900 66.880 ;
        RECT 125.180 65.795 125.380 66.085 ;
        RECT 125.180 64.115 125.380 64.405 ;
        RECT 125.180 64.160 125.380 64.360 ;
        RECT 125.180 64.160 125.380 66.040 ;
        RECT 125.180 65.840 125.380 66.040 ;
        RECT 65.180 66.635 65.380 66.925 ;
        RECT 65.180 54.875 65.380 55.165 ;
        RECT 65.180 54.920 65.380 55.120 ;
        RECT 65.180 54.920 65.380 66.880 ;
        RECT 65.180 66.680 65.380 66.880 ;
        RECT 61.340 66.635 61.540 66.925 ;
        RECT 61.340 66.680 61.540 66.880 ;
        RECT 61.340 66.680 61.540 68.140 ;
        RECT 61.340 67.895 61.540 68.185 ;
        RECT 61.340 67.940 61.540 68.140 ;
        RECT 71.900 59.075 72.100 59.365 ;
        RECT 71.900 52.775 72.100 53.065 ;
        RECT 71.900 52.820 72.100 53.020 ;
        RECT 71.900 52.820 72.100 59.320 ;
        RECT 71.900 59.120 72.100 59.320 ;
        RECT 99.260 59.495 99.460 59.785 ;
        RECT 99.260 57.395 99.460 57.685 ;
        RECT 99.260 57.440 99.460 57.640 ;
        RECT 99.260 57.440 99.460 59.740 ;
        RECT 99.260 59.540 99.460 59.740 ;
        RECT 64.220 69.155 64.420 69.445 ;
        RECT 64.220 67.055 64.420 67.345 ;
        RECT 64.220 67.100 64.420 67.300 ;
        RECT 64.220 67.100 64.420 69.400 ;
        RECT 64.220 69.200 64.420 69.400 ;
        RECT 103.100 66.635 103.300 66.925 ;
        RECT 103.100 56.555 103.300 56.845 ;
        RECT 103.100 56.600 103.300 56.800 ;
        RECT 103.100 56.600 103.300 66.880 ;
        RECT 103.100 66.680 103.300 66.880 ;
        RECT 115.100 56.555 115.300 56.845 ;
        RECT 115.100 56.600 115.300 56.800 ;
        RECT 115.100 56.600 115.300 68.980 ;
        RECT 115.100 68.735 115.300 69.025 ;
        RECT 115.100 68.780 115.300 68.980 ;
        RECT 90.140 102.755 90.340 103.045 ;
        RECT 90.140 41.015 90.340 41.305 ;
        RECT 90.140 41.060 90.340 41.260 ;
        RECT 90.140 41.060 90.340 103.000 ;
        RECT 90.140 102.800 90.340 103.000 ;
        RECT 75.740 110.735 75.940 111.025 ;
        RECT 75.740 72.515 75.940 72.805 ;
        RECT 75.740 72.560 75.940 72.760 ;
        RECT 75.740 72.560 75.940 110.980 ;
        RECT 75.740 110.780 75.940 110.980 ;
        RECT 73.820 103.595 74.020 103.885 ;
        RECT 73.820 65.375 74.020 65.665 ;
        RECT 73.820 65.420 74.020 65.620 ;
        RECT 73.820 65.420 74.020 103.840 ;
        RECT 73.820 103.640 74.020 103.840 ;
        RECT 99.260 88.895 99.460 89.185 ;
        RECT 99.260 64.115 99.460 64.405 ;
        RECT 99.260 64.160 99.460 64.360 ;
        RECT 99.260 64.160 99.460 89.140 ;
        RECT 99.260 88.940 99.460 89.140 ;
        RECT 98.300 104.435 98.500 104.725 ;
        RECT 98.300 79.235 98.500 79.525 ;
        RECT 98.300 79.280 98.500 79.480 ;
        RECT 98.300 79.280 98.500 104.680 ;
        RECT 98.300 104.480 98.500 104.680 ;
        RECT 81.500 98.135 81.700 98.425 ;
        RECT 81.500 48.155 81.700 48.445 ;
        RECT 81.500 48.200 81.700 48.400 ;
        RECT 81.500 48.200 81.700 98.380 ;
        RECT 81.500 98.180 81.700 98.380 ;
        RECT 101.660 111.995 101.860 112.285 ;
        RECT 101.660 104.015 101.860 104.305 ;
        RECT 101.660 104.060 101.860 104.260 ;
        RECT 101.660 104.060 101.860 112.240 ;
        RECT 101.660 112.040 101.860 112.240 ;
        RECT 100.700 127.115 100.900 127.405 ;
        RECT 100.700 84.695 100.900 84.985 ;
        RECT 100.700 84.740 100.900 84.940 ;
        RECT 100.700 84.740 100.900 127.360 ;
        RECT 100.700 127.160 100.900 127.360 ;
        RECT 84.380 126.275 84.580 126.565 ;
        RECT 84.380 117.455 84.580 117.745 ;
        RECT 84.380 117.500 84.580 117.700 ;
        RECT 84.380 117.500 84.580 126.520 ;
        RECT 84.380 126.320 84.580 126.520 ;
        RECT 118.460 114.935 118.660 115.225 ;
        RECT 118.460 107.795 118.660 108.085 ;
        RECT 118.460 107.840 118.660 108.040 ;
        RECT 118.460 107.840 118.660 115.180 ;
        RECT 118.460 114.980 118.660 115.180 ;
        RECT 96.860 127.115 97.060 127.405 ;
        RECT 96.860 117.455 97.060 117.745 ;
        RECT 96.860 117.500 97.060 117.700 ;
        RECT 96.860 117.500 97.060 127.360 ;
        RECT 96.860 127.160 97.060 127.360 ;
        RECT 101.660 119.555 101.860 119.845 ;
        RECT 101.660 117.455 101.860 117.745 ;
        RECT 101.660 117.500 101.860 117.700 ;
        RECT 101.660 117.500 101.860 119.800 ;
        RECT 101.660 119.600 101.860 119.800 ;
        RECT 109.820 126.695 110.020 126.985 ;
        RECT 109.820 119.975 110.020 120.265 ;
        RECT 109.820 120.020 110.020 120.220 ;
        RECT 109.820 120.020 110.020 126.940 ;
        RECT 109.820 126.740 110.020 126.940 ;
        RECT 106.940 117.455 107.140 117.745 ;
        RECT 106.940 109.475 107.140 109.765 ;
        RECT 106.940 109.520 107.140 109.720 ;
        RECT 106.940 109.520 107.140 117.700 ;
        RECT 106.940 117.500 107.140 117.700 ;
        RECT 59.900 58.235 60.100 58.525 ;
        RECT 59.900 56.975 60.100 57.265 ;
        RECT 59.900 57.020 60.100 57.220 ;
        RECT 59.900 57.020 60.100 58.480 ;
        RECT 59.900 58.280 60.100 58.480 ;
        RECT 59.900 58.280 60.100 72.760 ;
        RECT 59.900 72.515 60.100 72.805 ;
        RECT 59.900 72.560 60.100 72.760 ;
        RECT 69.980 73.355 70.180 73.645 ;
        RECT 69.980 73.400 70.180 73.600 ;
        RECT 69.980 73.400 70.180 110.140 ;
        RECT 69.980 109.895 70.180 110.185 ;
        RECT 69.980 109.940 70.180 110.140 ;
        RECT 70.940 20.855 71.140 21.145 ;
        RECT 70.940 20.900 71.140 21.100 ;
        RECT 70.940 20.900 71.140 56.800 ;
        RECT 70.940 26.315 71.140 26.605 ;
        RECT 70.940 26.360 71.140 26.560 ;
        RECT 70.940 56.555 71.140 56.845 ;
        RECT 70.940 56.600 71.140 56.800 ;
        RECT 92.060 27.995 92.260 28.285 ;
        RECT 92.060 28.040 92.260 28.240 ;
        RECT 92.060 28.040 92.260 39.580 ;
        RECT 92.060 39.335 92.260 39.625 ;
        RECT 92.060 39.380 92.260 39.580 ;
        RECT 132.380 43.115 132.580 43.405 ;
        RECT 132.380 32.195 132.580 32.485 ;
        RECT 132.380 32.240 132.580 32.440 ;
        RECT 132.380 32.240 132.580 43.360 ;
        RECT 132.380 43.160 132.580 43.360 ;
        RECT 132.380 43.160 132.580 47.140 ;
        RECT 132.380 46.895 132.580 47.185 ;
        RECT 132.380 46.940 132.580 47.140 ;
        RECT 93.980 34.715 94.180 35.005 ;
        RECT 93.980 33.035 94.180 33.325 ;
        RECT 93.980 33.080 94.180 33.280 ;
        RECT 93.980 33.080 94.180 34.960 ;
        RECT 93.980 34.760 94.180 34.960 ;
        RECT 68.540 96.035 68.740 96.325 ;
        RECT 68.540 96.080 68.740 96.280 ;
        RECT 68.540 96.080 68.740 107.620 ;
        RECT 68.540 107.375 68.740 107.665 ;
        RECT 68.540 107.420 68.740 107.620 ;
        RECT 109.820 107.375 110.020 107.665 ;
        RECT 109.820 103.595 110.020 103.885 ;
        RECT 109.820 103.640 110.020 103.840 ;
        RECT 109.820 103.640 110.020 107.620 ;
        RECT 109.820 107.420 110.020 107.620 ;
        RECT 121.820 73.355 122.020 73.645 ;
        RECT 121.820 32.195 122.020 32.485 ;
        RECT 121.820 32.240 122.020 32.440 ;
        RECT 121.820 32.240 122.020 73.600 ;
        RECT 121.820 69.155 122.020 69.445 ;
        RECT 121.820 69.200 122.020 69.400 ;
        RECT 121.820 73.400 122.020 73.600 ;
        RECT 130.940 103.595 131.140 103.885 ;
        RECT 130.940 101.915 131.140 102.205 ;
        RECT 130.940 101.960 131.140 102.160 ;
        RECT 130.940 101.960 131.140 103.840 ;
        RECT 130.940 103.640 131.140 103.840 ;
        RECT 133.820 101.915 134.020 102.205 ;
        RECT 133.820 87.635 134.020 87.925 ;
        RECT 133.820 87.680 134.020 87.880 ;
        RECT 133.820 87.680 134.020 102.160 ;
        RECT 133.820 101.960 134.020 102.160 ;
        RECT 142.460 65.795 142.660 66.085 ;
        RECT 142.460 65.840 142.660 66.040 ;
        RECT 142.460 65.840 142.660 69.400 ;
        RECT 142.460 69.155 142.660 69.445 ;
        RECT 142.460 69.200 142.660 69.400 ;
        RECT 72.860 50.675 73.060 50.965 ;
        RECT 72.860 33.875 73.060 34.165 ;
        RECT 72.860 33.920 73.060 34.120 ;
        RECT 72.860 33.920 73.060 50.920 ;
        RECT 72.860 40.175 73.060 40.465 ;
        RECT 72.860 40.220 73.060 40.420 ;
        RECT 72.860 50.720 73.060 50.920 ;
        RECT 72.860 50.720 73.060 71.920 ;
        RECT 72.860 71.675 73.060 71.965 ;
        RECT 72.860 71.720 73.060 71.920 ;
        RECT 90.620 37.655 90.820 37.945 ;
        RECT 90.620 37.700 90.820 37.900 ;
        RECT 90.620 37.700 90.820 40.420 ;
        RECT 90.620 40.175 90.820 40.465 ;
        RECT 90.620 40.220 90.820 40.420 ;
        RECT 100.220 73.355 100.420 73.645 ;
        RECT 100.220 73.400 100.420 73.600 ;
        RECT 100.220 73.400 100.420 78.220 ;
        RECT 100.220 77.975 100.420 78.265 ;
        RECT 100.220 78.020 100.420 78.220 ;
        RECT 127.580 71.675 127.780 71.965 ;
        RECT 127.580 69.995 127.780 70.285 ;
        RECT 127.580 70.040 127.780 70.240 ;
        RECT 127.580 70.040 127.780 71.920 ;
        RECT 127.580 71.720 127.780 71.920 ;
        RECT 139.100 65.795 139.300 66.085 ;
        RECT 139.100 49.835 139.300 50.125 ;
        RECT 139.100 49.880 139.300 50.080 ;
        RECT 139.100 49.880 139.300 66.040 ;
        RECT 139.100 65.840 139.300 66.040 ;
        RECT 139.100 65.840 139.300 70.240 ;
        RECT 139.100 69.995 139.300 70.285 ;
        RECT 139.100 70.040 139.300 70.240 ;
        RECT 58.460 65.795 58.660 66.085 ;
        RECT 58.460 51.515 58.660 51.805 ;
        RECT 58.460 51.560 58.660 51.760 ;
        RECT 58.460 51.560 58.660 66.040 ;
        RECT 58.460 54.035 58.660 54.325 ;
        RECT 58.460 54.080 58.660 54.280 ;
        RECT 58.460 65.840 58.660 66.040 ;
        RECT 58.460 65.840 58.660 98.380 ;
        RECT 58.460 98.135 58.660 98.425 ;
        RECT 58.460 98.180 58.660 98.380 ;
        RECT 186.620 144.755 186.820 145.045 ;
        RECT 186.620 144.800 186.820 145.000 ;
        RECT 186.620 144.800 186.820 154.240 ;
        RECT 186.620 154.040 187.300 154.240 ;
        RECT 187.100 154.040 187.300 154.240 ;
        RECT 182.780 145.595 182.980 145.885 ;
        RECT 182.780 145.640 182.980 145.840 ;
        RECT 182.780 145.640 182.980 154.240 ;
        RECT 182.780 154.040 183.460 154.240 ;
        RECT 183.260 154.040 183.460 154.240 ;
        RECT 56.060 154.040 56.740 154.240 ;
        RECT 56.060 153.995 56.260 154.285 ;
        RECT 56.060 154.040 56.260 154.240 ;
        RECT 56.540 154.040 56.740 154.240 ;
        RECT 52.220 154.040 52.900 154.240 ;
        RECT 52.220 153.995 52.420 154.285 ;
        RECT 52.220 154.040 52.420 154.240 ;
        RECT 52.700 154.040 52.900 154.240 ;
        RECT 48.860 154.040 49.540 154.240 ;
        RECT 48.860 154.040 49.060 154.240 ;
        RECT 49.340 153.995 49.540 154.285 ;
        RECT 49.340 154.040 49.540 154.240 ;
        RECT 45.020 154.040 45.700 154.240 ;
        RECT 45.020 154.040 45.220 154.240 ;
        RECT 45.500 153.995 45.700 154.285 ;
        RECT 45.500 154.040 45.700 154.240 ;
        RECT 41.180 154.040 41.860 154.240 ;
        RECT 41.180 154.040 41.380 154.240 ;
        RECT 41.660 153.995 41.860 154.285 ;
        RECT 41.660 154.040 41.860 154.240 ;
        RECT 37.340 154.040 38.020 154.240 ;
        RECT 37.340 154.040 37.540 154.240 ;
        RECT 37.820 153.995 38.020 154.285 ;
        RECT 37.820 154.040 38.020 154.240 ;
        RECT 33.020 154.040 33.700 154.240 ;
        RECT 33.020 153.995 33.220 154.285 ;
        RECT 33.020 154.040 33.220 154.240 ;
        RECT 33.500 154.040 33.700 154.240 ;
        RECT 29.180 154.040 29.860 154.240 ;
        RECT 29.180 153.995 29.380 154.285 ;
        RECT 29.180 154.040 29.380 154.240 ;
        RECT 29.660 154.040 29.860 154.240 ;
        RECT 86.780 154.040 87.460 154.240 ;
        RECT 86.780 153.995 86.980 154.285 ;
        RECT 86.780 154.040 86.980 154.240 ;
        RECT 87.260 154.040 87.460 154.240 ;
        RECT 83.420 154.040 84.100 154.240 ;
        RECT 83.420 154.040 83.620 154.240 ;
        RECT 83.900 140.135 84.100 140.425 ;
        RECT 83.900 140.180 84.100 140.380 ;
        RECT 83.900 140.180 84.100 154.240 ;
        RECT 79.580 154.040 80.260 154.240 ;
        RECT 79.580 154.040 79.780 154.240 ;
        RECT 80.060 153.995 80.260 154.285 ;
        RECT 80.060 154.040 80.260 154.240 ;
        RECT 75.740 154.040 76.420 154.240 ;
        RECT 75.740 154.040 75.940 154.240 ;
        RECT 76.220 153.995 76.420 154.285 ;
        RECT 76.220 154.040 76.420 154.240 ;
        RECT 71.420 154.040 72.100 154.240 ;
        RECT 71.420 153.995 71.620 154.285 ;
        RECT 71.420 154.040 71.620 154.240 ;
        RECT 71.900 154.040 72.100 154.240 ;
        RECT 68.060 154.040 68.740 154.240 ;
        RECT 68.060 154.040 68.260 154.240 ;
        RECT 68.540 146.435 68.740 146.725 ;
        RECT 68.540 146.480 68.740 146.680 ;
        RECT 68.540 146.480 68.740 154.240 ;
        RECT 63.740 154.040 64.420 154.240 ;
        RECT 63.740 153.575 63.940 153.865 ;
        RECT 63.740 153.620 63.940 153.820 ;
        RECT 63.740 153.620 63.940 154.240 ;
        RECT 64.220 154.040 64.420 154.240 ;
        RECT 59.900 154.040 60.580 154.240 ;
        RECT 59.900 153.575 60.100 153.865 ;
        RECT 59.900 153.620 60.100 153.820 ;
        RECT 59.900 153.620 60.100 154.240 ;
        RECT 60.380 154.040 60.580 154.240 ;
        RECT 117.980 154.040 118.660 154.240 ;
        RECT 117.980 154.040 118.180 154.240 ;
        RECT 118.460 153.995 118.660 154.285 ;
        RECT 118.460 154.040 118.660 154.240 ;
        RECT 113.660 154.040 114.340 154.240 ;
        RECT 113.660 153.995 113.860 154.285 ;
        RECT 113.660 154.040 113.860 154.240 ;
        RECT 114.140 154.040 114.340 154.240 ;
        RECT 109.820 154.040 110.500 154.240 ;
        RECT 109.820 153.995 110.020 154.285 ;
        RECT 109.820 154.040 110.020 154.240 ;
        RECT 110.300 154.040 110.500 154.240 ;
        RECT 105.980 154.040 106.660 154.240 ;
        RECT 105.980 153.995 106.180 154.285 ;
        RECT 105.980 154.040 106.180 154.240 ;
        RECT 106.460 154.040 106.660 154.240 ;
        RECT 102.620 154.040 103.300 154.240 ;
        RECT 102.620 154.040 102.820 154.240 ;
        RECT 103.100 153.995 103.300 154.285 ;
        RECT 103.100 154.040 103.300 154.240 ;
        RECT 98.300 154.040 98.980 154.240 ;
        RECT 98.300 139.295 98.500 139.585 ;
        RECT 98.300 139.340 98.500 139.540 ;
        RECT 98.300 139.340 98.500 154.240 ;
        RECT 98.780 154.040 98.980 154.240 ;
        RECT 94.940 154.040 95.620 154.240 ;
        RECT 94.940 154.040 95.140 154.240 ;
        RECT 95.420 153.155 95.620 153.445 ;
        RECT 95.420 153.200 95.620 153.400 ;
        RECT 95.420 153.200 95.620 154.240 ;
        RECT 90.620 154.040 91.300 154.240 ;
        RECT 90.620 153.995 90.820 154.285 ;
        RECT 90.620 154.040 90.820 154.240 ;
        RECT 91.100 154.040 91.300 154.240 ;
  END
END tt_um_microlane_demo
END LIBRARY

